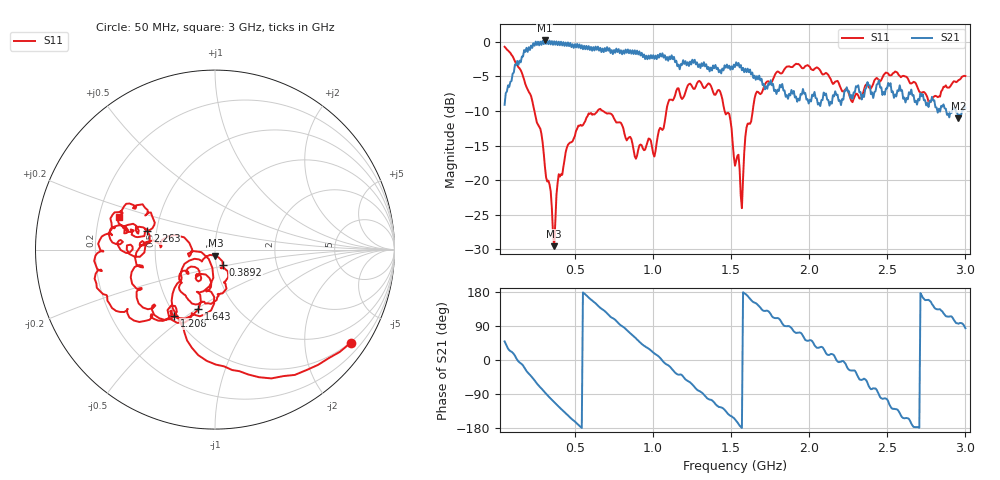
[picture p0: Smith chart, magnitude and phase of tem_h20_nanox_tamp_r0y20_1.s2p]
! nanovna_capture.py 2026-10-26T21:15:58+0900
! NanoVNA-F_V2 fw 0.6.0 SN 4A3639384505514B
! cal: load open short thru cal'ed  over 50000000-3000000000 Hz, 201 points
! points 401, avg 4
! TEM h=20, tampered Nano X, flat back down, 0 deg, moved 20 mm along the cell toward PORT 2
# HZ S RI R 50
! S12 and S22 are not measured (written as 0)
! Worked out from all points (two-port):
!   401 points, 50 MHz to 3 GHz, reference 50 ohm
!   highest |S21| = 0.16 dB at 308.1 MHz (marker M1); lowest = -11.1 dB at 2.956 GHz (marker M2)
!   |S21| within 3 dB of the highest: 130.7 MHz to 131.6 MHz (898.5 kHz wide, 0.685 % of centre); 154.6 MHz to 1.14 GHz (985.6 MHz wide, 152 % of centre) (the widest 2 of 8)
!   lowest |S11| = -29.5 dB at 367.1 MHz (marker M3), VSWR 1.07, Z = 50.1 - j3.34 ohm
!   |S11| at or under -10 dB: 240.7 MHz to 645.3 MHz (404.6 MHz wide, 91.3 % of centre); 678.3 MHz to 1.086 GHz (407.4 MHz wide, 46.2 % of centre); 1.458 GHz to 1.638 GHz (180.1 MHz wide, 11.6 % of centre)
!   S12 and S22 are empty: the file has one direction only
!   S11 on the Smith chart (normalised r, x): 50 MHz: 0.48, -3.15; 389.2 MHz: 1.07, -0.18; 1.208 GHz: 0.50, -0.45; 1.643 GHz: 0.68, -0.51; 2.263 GHz: 0.44, +0.11; 3 GHz: 0.29, +0.15
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5e7  0.7555 -0.5198  0.2298 0.2641  0 0  0 0
1.01625e8  0.3138 -0.7176  0.5538 0.1934  0 0  0 0
1.75375e8  -0.1559 -0.5056  0.8202 -0.2851  0 0  0 0
3.08125e8  -0.114 -0.0511  0.0795 -1.016  0 0  0 0
3.67125e8  0.00201 -0.0333  -0.3613 -0.9377  0 0  0 0
3.8925e8  0.0428 -0.0851  -0.4734 -0.8153  0 0  0 0
5.44125e8  0.0194 -0.2462  -0.9416 -0.0121  0 0  0 0
7.80125e8  -0.1866 -0.1831  -0.1013 0.8762  0 0  0 0
9.12875e8  -0.0981 -0.1485  0.57 0.6291  0 0  0 0
1.03825e9  -0.0339 -0.2271  0.757 0.1145  0 0  0 0
1.207875e9  -0.2261 -0.3683  0.4526 -0.5641  0 0  0 0
1.429125e9  -0.4376 -0.0146  -0.3501 -0.5146  0 0  0 0
1.525e9  -0.127 0.000551  -0.6018 -0.26  0 0  0 0
1.56925e9  -0.0348 -0.0523  -0.6212 -0.00776  0 0  0 0
1.643e9  -0.0924 -0.3327  -0.484 0.2513  0 0  0 0
1.827375e9  -0.4889 -0.3363  -0.0548 0.4912  0 0  0 0
2.019125e9  -0.6258 -0.00584  0.267 0.3165  0 0  0 0
2.2625e9  -0.3768 0.1042  0.3481 -0.1808  0 0  0 0
2.51325e9  -0.5573 0.1239  -0.2212 -0.4259  0 0  0 0
2.712375e9  -0.3753 0.2087  -0.4232 0.026  0 0  0 0
2.95575e9  -0.5129 0.1217  -0.0273 0.2781  0 0  0 0
3e9  -0.533 0.184  0.0353 0.331  0 0  0 0
